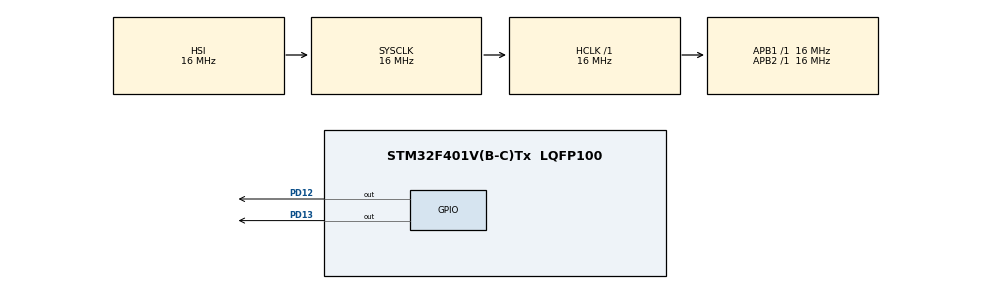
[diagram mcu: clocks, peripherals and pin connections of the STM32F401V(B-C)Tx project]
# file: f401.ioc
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FREERTOS.Tasks01=defaultTask,24,128,StartDefaultTask,Default,NULL,Dynamic,NULL,NULL
FREERTOS.configUSE_IDLE_HOOK=1
FREERTOS.configUSE_NEWLIB_REENTRANT=1
Mcu.Family=STM32F4
Mcu.Name=STM32F401V(B-C)Tx
Mcu.Package=LQFP100
NVIC.PriorityGroup=NVIC_PRIORITYGROUP_4
NVIC.TIM1_BRK_TIM9_IRQn=true\:15\:0\:false\:false\:true\:false\:false\:true\:true
NVIC.TimeBase=TIM1_BRK_TIM9_IRQn
NVIC.TimeBaseIP=TIM9
PD12.Signal=GPIO_Output
PD13.Signal=GPIO_Output
ProjectManager.HeapSize=0x200
ProjectManager.StackSize=0x400
ProjectManager.TargetToolchain=STM32CubeIDE
RCC.AHBFreq_Value=16000000
RCC.APB1Freq_Value=16000000
RCC.APB2Freq_Value=16000000
RCC.CortexFreq_Value=16000000
RCC.HSE_VALUE=25000000
RCC.HSI_VALUE=16000000
RCC.LSE_VALUE=32768
RCC.SYSCLKFreq_VALUE=16000000
RCC.VCOOutputFreq_Value=192000000
VP_FREERTOS_VS_CMSIS_V2.Mode=CMSIS_V2
VP_SYS_VS_tim9.Mode=TIM9
board=custom

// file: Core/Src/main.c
/* USER CODE BEGIN Header */
/**
  ******************************************************************************
  * @file           : main.c
  * @brief          : Main program body
  ******************************************************************************
  * @attention
  *
  * Copyright (c) 2026 STMicroelectronics.
  * All rights reserved.
  *
  * This software is licensed under terms that can be found in the LICENSE file
  * in the root directory of this software component.
  * If no LICENSE file comes with this software, it is provided AS-IS.
  *
  ******************************************************************************
  */

/* USER CODE END Header */
#include "main.h"
#include "cmsis_os.h"
#include "queue.h"
#include "semphr.h"
#include <stdio.h>
extern void initialise_monitor_handles(void);

#ifdef MAIN1

void SystemClock_Config(void);
static void MX_GPIO_Init(void);
void StartDefaultTask(void *argument);

SemaphoreHandle_t   Sem1;
TaskHandle_t        hTask1,hTask2;
QueueHandle_t       Queue1,Queuedisplay;
SemaphoreHandle_t wMutex;

void Task1(void *p);
void Task2(void *p);
void Task3(void *p);
void Task4(void *p);

int main(void)
{
#ifdef DEBUG
  initialise_monitor_handles();
  printf("LAB RTOS------------------- \n");
#endif
  /* Reset of all peripherals, Initializes the Flash interface and the Systick. */
  HAL_Init();

  /* Configure the system clock */
  SystemClock_Config();

  /* Initialize all configured peripherals */
  MX_GPIO_Init();

  /* Create a queue capable of containing 10 unsigned long values. */
  Queue1 = xQueueCreate( 10, sizeof( uint32_t ) );

  wMutex= xSemaphoreCreateMutex();

   xTaskCreate(Task1,"T1",128,NULL,2,NULL);
   xTaskCreate(Task2,"T2",128,    NULL,2,NULL);
   xTaskCreate(Task3,"T3",128,    NULL,2,NULL);
   xTaskCreate(Task4,"T4",128,    NULL,2,NULL);
   /* Create the thread(s) */
   vTaskStartScheduler();

  while (1)
  {

  }
}

/*Perdidic Task*/
void Task1(void *p) //P1
{

  while(1)
  {
    printf("TAsk 1 is running....\n");
    HAL_GPIO_TogglePin(GPIOD,GPIO_PIN_12);
    vTaskDelay(1000);
  }
}

/*Perdidic Task*/
void Task2(void *p) //P1
{

  while(1)
  {
    printf("TAsk 2 is running....\n");
    HAL_GPIO_TogglePin(GPIOD,GPIO_PIN_13);
    vTaskDelay(500);
  }
}
/*Perdidic Task*/
void Task3(void *p) //P1
{

  while(1)
  {
   printf("TAsk 3 is running....\n");
    HAL_GPIO_TogglePin(GPIOD,GPIO_PIN_14);
    vTaskDelay(300);
  }
}

/*Perdidic Task*/
void Task4(void *p) //P1
{

  while(1)
  {
    printf("TAsk 4 is running....\n");
    HAL_GPIO_TogglePin(GPIOD,GPIO_PIN_15);
    vTaskDelay(700);
  }
}

void SystemClock_Config(void)
{
  RCC_OscInitTypeDef RCC_OscInitStruct = {0};
  RCC_ClkInitTypeDef RCC_ClkInitStruct = {0};

  /** Configure the main internal regulator output voltage
  */
  __HAL_RCC_PWR_CLK_ENABLE();
  __HAL_PWR_VOLTAGESCALING_CONFIG(PWR_REGULATOR_VOLTAGE_SCALE1);

  /** Initializes the RCC Oscillators according to the specified parameters
  * in the RCC_OscInitTypeDef structure.
  */
  RCC_OscInitStruct.OscillatorType = RCC_OSCILLATORTYPE_HSI;
  RCC_OscInitStruct.HSIState = RCC_HSI_ON;
  RCC_OscInitStruct.HSICalibrationValue = RCC_HSICALIBRATION_DEFAULT;
  RCC_OscInitStruct.PLL.PLLState = RCC_PLL_NONE;
  if (HAL_RCC_OscConfig(&RCC_OscInitStruct) != HAL_OK)
  {
    Error_Handler();
  }

  /** Initializes the CPU, AHB and APB buses clocks
  */
  RCC_ClkInitStruct.ClockType = RCC_CLOCKTYPE_HCLK|RCC_CLOCKTYPE_SYSCLK
                              |RCC_CLOCKTYPE_PCLK1|RCC_CLOCKTYPE_PCLK2;
  RCC_ClkInitStruct.SYSCLKSource = RCC_SYSCLKSOURCE_HSI;
  RCC_ClkInitStruct.AHBCLKDivider = RCC_SYSCLK_DIV1;
  RCC_ClkInitStruct.APB1CLKDivider = RCC_HCLK_DIV1;
  RCC_ClkInitStruct.APB2CLKDivider = RCC_HCLK_DIV1;

  if (HAL_RCC_ClockConfig(&RCC_ClkInitStruct, FLASH_LATENCY_0) != HAL_OK)
  {
    Error_Handler();
  }
}

static void MX_GPIO_Init(void)
{
  GPIO_InitTypeDef GPIO_InitStruct = {0};

  /* GPIO Ports Clock Enable */
  __HAL_RCC_GPIOA_CLK_ENABLE();
  __HAL_RCC_GPIOD_CLK_ENABLE();

  /*Configure GPIO pin Output Level */
  HAL_GPIO_WritePin(GPIOD, GPIO_PIN_12|GPIO_PIN_13|GPIO_PIN_14|GPIO_PIN_15, GPIO_PIN_RESET);

  /*Configure GPIO pin : PA0 */
  GPIO_InitStruct.Pin = GPIO_PIN_0;
  GPIO_InitStruct.Mode = GPIO_MODE_IT_RISING;
  GPIO_InitStruct.Pull = GPIO_NOPULL;
  HAL_GPIO_Init(GPIOA, &GPIO_InitStruct);

  /*Configure GPIO pins : PD12 PD13 PD14 PD15 */
  GPIO_InitStruct.Pin = GPIO_PIN_12|GPIO_PIN_13|GPIO_PIN_14|GPIO_PIN_15;
  GPIO_InitStruct.Mode = GPIO_MODE_OUTPUT_PP;
  GPIO_InitStruct.Pull = GPIO_NOPULL;
  GPIO_InitStruct.Speed = GPIO_SPEED_FREQ_LOW;
  HAL_GPIO_Init(GPIOD, &GPIO_InitStruct);

  /* EXTI interrupt init*/
  HAL_NVIC_SetPriority(EXTI0_IRQn, 5, 0);
  HAL_NVIC_EnableIRQ(EXTI0_IRQn);

}

void StartDefaultTask(void *argument)
{
  for(;;)
  {
    osDelay(1);
  }
}

void HAL_TIM_PeriodElapsedCallback(TIM_HandleTypeDef *htim)
{
  if (htim->Instance == TIM9) {
    HAL_IncTick();
  }
}

void Error_Handler(void)
{
  while(1)
  {
  }
}

#endif
